VERSION 5.7 ;
  NOWIREEXTENSIONATPIN ON ;
  DIVIDERCHAR "/" ;
  BUSBITCHARS "[]" ;
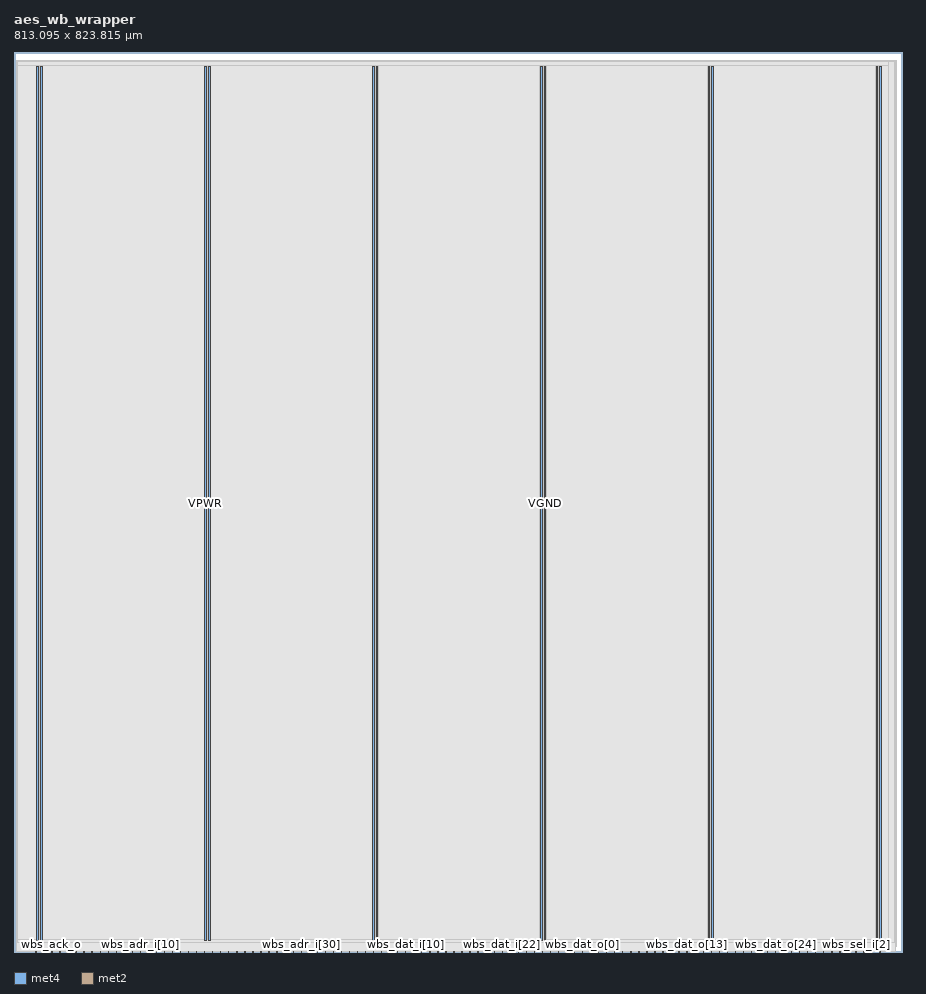
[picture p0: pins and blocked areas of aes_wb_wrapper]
MACRO aes_wb_wrapper
  CLASS BLOCK ;
  FOREIGN aes_wb_wrapper ;
  ORIGIN 0.000 0.000 ;
  SIZE 813.095 BY 823.815 ;
  PIN VGND
    DIRECTION INOUT ;
    USE GROUND ;
    PORT
      LAYER met4 ;
        RECT 24.340 10.640 25.940 810.800 ;
    END
    PORT
      LAYER met4 ;
        RECT 177.940 10.640 179.540 810.800 ;
    END
    PORT
      LAYER met4 ;
        RECT 331.540 10.640 333.140 810.800 ;
    END
    PORT
      LAYER met4 ;
        RECT 485.140 10.640 486.740 810.800 ;
    END
    PORT
      LAYER met4 ;
        RECT 638.740 10.640 640.340 810.800 ;
    END
    PORT
      LAYER met4 ;
        RECT 792.340 10.640 793.940 810.800 ;
    END
  END VGND
  PIN VPWR
    DIRECTION INOUT ;
    USE POWER ;
    PORT
      LAYER met4 ;
        RECT 21.040 10.640 22.640 810.800 ;
    END
    PORT
      LAYER met4 ;
        RECT 174.640 10.640 176.240 810.800 ;
    END
    PORT
      LAYER met4 ;
        RECT 328.240 10.640 329.840 810.800 ;
    END
    PORT
      LAYER met4 ;
        RECT 481.840 10.640 483.440 810.800 ;
    END
    PORT
      LAYER met4 ;
        RECT 635.440 10.640 637.040 810.800 ;
    END
    PORT
      LAYER met4 ;
        RECT 789.040 10.640 790.640 810.800 ;
    END
  END VPWR
  PIN wb_clk_i
    DIRECTION INPUT ;
    USE SIGNAL ;
    ANTENNAGATEAREA 1.286700 ;
    ANTENNADIFFAREA 0.434700 ;
    PORT
      LAYER met2 ;
        RECT 19.870 0.000 20.150 0.280 ;
    END
  END wb_clk_i
  PIN wb_rst_i
    DIRECTION INPUT ;
    USE SIGNAL ;
    ANTENNAGATEAREA 0.593700 ;
    ANTENNADIFFAREA 0.434700 ;
    PORT
      LAYER met2 ;
        RECT 27.230 0.000 27.510 0.280 ;
    END
  END wb_rst_i
  PIN wbs_ack_o
    DIRECTION OUTPUT ;
    USE SIGNAL ;
    ANTENNADIFFAREA 2.673000 ;
    PORT
      LAYER met2 ;
        RECT 34.590 0.000 34.870 0.280 ;
    END
  END wbs_ack_o
  PIN wbs_adr_i[0]
    DIRECTION INPUT ;
    USE SIGNAL ;
    PORT
      LAYER met2 ;
        RECT 41.950 0.000 42.230 0.280 ;
    END
  END wbs_adr_i[0]
  PIN wbs_adr_i[10]
    DIRECTION INPUT ;
    USE SIGNAL ;
    PORT
      LAYER met2 ;
        RECT 115.550 0.000 115.830 0.280 ;
    END
  END wbs_adr_i[10]
  PIN wbs_adr_i[11]
    DIRECTION INPUT ;
    USE SIGNAL ;
    PORT
      LAYER met2 ;
        RECT 122.910 0.000 123.190 0.280 ;
    END
  END wbs_adr_i[11]
  PIN wbs_adr_i[12]
    DIRECTION INPUT ;
    USE SIGNAL ;
    PORT
      LAYER met2 ;
        RECT 130.270 0.000 130.550 0.280 ;
    END
  END wbs_adr_i[12]
  PIN wbs_adr_i[13]
    DIRECTION INPUT ;
    USE SIGNAL ;
    PORT
      LAYER met2 ;
        RECT 137.630 0.000 137.910 0.280 ;
    END
  END wbs_adr_i[13]
  PIN wbs_adr_i[14]
    DIRECTION INPUT ;
    USE SIGNAL ;
    PORT
      LAYER met2 ;
        RECT 144.990 0.000 145.270 0.280 ;
    END
  END wbs_adr_i[14]
  PIN wbs_adr_i[15]
    DIRECTION INPUT ;
    USE SIGNAL ;
    PORT
      LAYER met2 ;
        RECT 152.350 0.000 152.630 0.280 ;
    END
  END wbs_adr_i[15]
  PIN wbs_adr_i[16]
    DIRECTION INPUT ;
    USE SIGNAL ;
    PORT
      LAYER met2 ;
        RECT 159.710 0.000 159.990 0.280 ;
    END
  END wbs_adr_i[16]
  PIN wbs_adr_i[17]
    DIRECTION INPUT ;
    USE SIGNAL ;
    PORT
      LAYER met2 ;
        RECT 167.070 0.000 167.350 0.280 ;
    END
  END wbs_adr_i[17]
  PIN wbs_adr_i[18]
    DIRECTION INPUT ;
    USE SIGNAL ;
    PORT
      LAYER met2 ;
        RECT 174.430 0.000 174.710 0.280 ;
    END
  END wbs_adr_i[18]
  PIN wbs_adr_i[19]
    DIRECTION INPUT ;
    USE SIGNAL ;
    PORT
      LAYER met2 ;
        RECT 181.790 0.000 182.070 0.280 ;
    END
  END wbs_adr_i[19]
  PIN wbs_adr_i[1]
    DIRECTION INPUT ;
    USE SIGNAL ;
    PORT
      LAYER met2 ;
        RECT 49.310 0.000 49.590 0.280 ;
    END
  END wbs_adr_i[1]
  PIN wbs_adr_i[20]
    DIRECTION INPUT ;
    USE SIGNAL ;
    PORT
      LAYER met2 ;
        RECT 189.150 0.000 189.430 0.280 ;
    END
  END wbs_adr_i[20]
  PIN wbs_adr_i[21]
    DIRECTION INPUT ;
    USE SIGNAL ;
    PORT
      LAYER met2 ;
        RECT 196.510 0.000 196.790 0.280 ;
    END
  END wbs_adr_i[21]
  PIN wbs_adr_i[22]
    DIRECTION INPUT ;
    USE SIGNAL ;
    PORT
      LAYER met2 ;
        RECT 203.870 0.000 204.150 0.280 ;
    END
  END wbs_adr_i[22]
  PIN wbs_adr_i[23]
    DIRECTION INPUT ;
    USE SIGNAL ;
    PORT
      LAYER met2 ;
        RECT 211.230 0.000 211.510 0.280 ;
    END
  END wbs_adr_i[23]
  PIN wbs_adr_i[24]
    DIRECTION INPUT ;
    USE SIGNAL ;
    PORT
      LAYER met2 ;
        RECT 218.590 0.000 218.870 0.280 ;
    END
  END wbs_adr_i[24]
  PIN wbs_adr_i[25]
    DIRECTION INPUT ;
    USE SIGNAL ;
    PORT
      LAYER met2 ;
        RECT 225.950 0.000 226.230 0.280 ;
    END
  END wbs_adr_i[25]
  PIN wbs_adr_i[26]
    DIRECTION INPUT ;
    USE SIGNAL ;
    PORT
      LAYER met2 ;
        RECT 233.310 0.000 233.590 0.280 ;
    END
  END wbs_adr_i[26]
  PIN wbs_adr_i[27]
    DIRECTION INPUT ;
    USE SIGNAL ;
    PORT
      LAYER met2 ;
        RECT 240.670 0.000 240.950 0.280 ;
    END
  END wbs_adr_i[27]
  PIN wbs_adr_i[28]
    DIRECTION INPUT ;
    USE SIGNAL ;
    PORT
      LAYER met2 ;
        RECT 248.030 0.000 248.310 0.280 ;
    END
  END wbs_adr_i[28]
  PIN wbs_adr_i[29]
    DIRECTION INPUT ;
    USE SIGNAL ;
    PORT
      LAYER met2 ;
        RECT 255.390 0.000 255.670 0.280 ;
    END
  END wbs_adr_i[29]
  PIN wbs_adr_i[2]
    DIRECTION INPUT ;
    USE SIGNAL ;
    ANTENNAGATEAREA 0.560700 ;
    ANTENNADIFFAREA 0.434700 ;
    PORT
      LAYER met2 ;
        RECT 56.670 0.000 56.950 0.280 ;
    END
  END wbs_adr_i[2]
  PIN wbs_adr_i[30]
    DIRECTION INPUT ;
    USE SIGNAL ;
    PORT
      LAYER met2 ;
        RECT 262.750 0.000 263.030 0.280 ;
    END
  END wbs_adr_i[30]
  PIN wbs_adr_i[31]
    DIRECTION INPUT ;
    USE SIGNAL ;
    PORT
      LAYER met2 ;
        RECT 270.110 0.000 270.390 0.280 ;
    END
  END wbs_adr_i[31]
  PIN wbs_adr_i[3]
    DIRECTION INPUT ;
    USE SIGNAL ;
    ANTENNAGATEAREA 0.560700 ;
    ANTENNADIFFAREA 0.434700 ;
    PORT
      LAYER met2 ;
        RECT 64.030 0.000 64.310 0.280 ;
    END
  END wbs_adr_i[3]
  PIN wbs_adr_i[4]
    DIRECTION INPUT ;
    USE SIGNAL ;
    ANTENNAGATEAREA 0.560700 ;
    ANTENNADIFFAREA 0.434700 ;
    PORT
      LAYER met2 ;
        RECT 71.390 0.000 71.670 0.280 ;
    END
  END wbs_adr_i[4]
  PIN wbs_adr_i[5]
    DIRECTION INPUT ;
    USE SIGNAL ;
    ANTENNAGATEAREA 0.560700 ;
    ANTENNADIFFAREA 0.434700 ;
    PORT
      LAYER met2 ;
        RECT 78.750 0.000 79.030 0.280 ;
    END
  END wbs_adr_i[5]
  PIN wbs_adr_i[6]
    DIRECTION INPUT ;
    USE SIGNAL ;
    ANTENNAGATEAREA 0.560700 ;
    ANTENNADIFFAREA 0.434700 ;
    PORT
      LAYER met2 ;
        RECT 86.110 0.000 86.390 0.280 ;
    END
  END wbs_adr_i[6]
  PIN wbs_adr_i[7]
    DIRECTION INPUT ;
    USE SIGNAL ;
    ANTENNAGATEAREA 0.560700 ;
    ANTENNADIFFAREA 0.434700 ;
    PORT
      LAYER met2 ;
        RECT 93.470 0.000 93.750 0.280 ;
    END
  END wbs_adr_i[7]
  PIN wbs_adr_i[8]
    DIRECTION INPUT ;
    USE SIGNAL ;
    ANTENNAGATEAREA 0.560700 ;
    ANTENNADIFFAREA 0.434700 ;
    PORT
      LAYER met2 ;
        RECT 100.830 0.000 101.110 0.280 ;
    END
  END wbs_adr_i[8]
  PIN wbs_adr_i[9]
    DIRECTION INPUT ;
    USE SIGNAL ;
    ANTENNAGATEAREA 0.647700 ;
    ANTENNADIFFAREA 0.434700 ;
    PORT
      LAYER met2 ;
        RECT 108.190 0.000 108.470 0.280 ;
    END
  END wbs_adr_i[9]
  PIN wbs_cyc_i
    DIRECTION INPUT ;
    USE SIGNAL ;
    ANTENNAGATEAREA 0.560700 ;
    ANTENNADIFFAREA 0.434700 ;
    PORT
      LAYER met2 ;
        RECT 277.470 0.000 277.750 0.280 ;
    END
  END wbs_cyc_i
  PIN wbs_dat_i[0]
    DIRECTION INPUT ;
    USE SIGNAL ;
    ANTENNAGATEAREA 0.560700 ;
    ANTENNADIFFAREA 0.434700 ;
    PORT
      LAYER met2 ;
        RECT 284.830 0.000 285.110 0.280 ;
    END
  END wbs_dat_i[0]
  PIN wbs_dat_i[10]
    DIRECTION INPUT ;
    USE SIGNAL ;
    ANTENNAGATEAREA 0.560700 ;
    ANTENNADIFFAREA 0.434700 ;
    PORT
      LAYER met2 ;
        RECT 358.430 0.000 358.710 0.280 ;
    END
  END wbs_dat_i[10]
  PIN wbs_dat_i[11]
    DIRECTION INPUT ;
    USE SIGNAL ;
    ANTENNAGATEAREA 0.560700 ;
    ANTENNADIFFAREA 0.434700 ;
    PORT
      LAYER met2 ;
        RECT 365.790 0.000 366.070 0.280 ;
    END
  END wbs_dat_i[11]
  PIN wbs_dat_i[12]
    DIRECTION INPUT ;
    USE SIGNAL ;
    ANTENNAGATEAREA 0.560700 ;
    ANTENNADIFFAREA 0.434700 ;
    PORT
      LAYER met2 ;
        RECT 373.150 0.000 373.430 0.280 ;
    END
  END wbs_dat_i[12]
  PIN wbs_dat_i[13]
    DIRECTION INPUT ;
    USE SIGNAL ;
    ANTENNAGATEAREA 0.560700 ;
    ANTENNADIFFAREA 0.434700 ;
    PORT
      LAYER met2 ;
        RECT 380.510 0.000 380.790 0.280 ;
    END
  END wbs_dat_i[13]
  PIN wbs_dat_i[14]
    DIRECTION INPUT ;
    USE SIGNAL ;
    ANTENNAGATEAREA 0.560700 ;
    ANTENNADIFFAREA 0.434700 ;
    PORT
      LAYER met2 ;
        RECT 387.870 0.000 388.150 0.280 ;
    END
  END wbs_dat_i[14]
  PIN wbs_dat_i[15]
    DIRECTION INPUT ;
    USE SIGNAL ;
    ANTENNAGATEAREA 0.560700 ;
    ANTENNADIFFAREA 0.434700 ;
    PORT
      LAYER met2 ;
        RECT 395.230 0.000 395.510 0.280 ;
    END
  END wbs_dat_i[15]
  PIN wbs_dat_i[16]
    DIRECTION INPUT ;
    USE SIGNAL ;
    ANTENNAGATEAREA 0.560700 ;
    ANTENNADIFFAREA 0.434700 ;
    PORT
      LAYER met2 ;
        RECT 402.590 0.000 402.870 0.280 ;
    END
  END wbs_dat_i[16]
  PIN wbs_dat_i[17]
    DIRECTION INPUT ;
    USE SIGNAL ;
    ANTENNAGATEAREA 0.560700 ;
    ANTENNADIFFAREA 0.434700 ;
    PORT
      LAYER met2 ;
        RECT 409.950 0.000 410.230 0.280 ;
    END
  END wbs_dat_i[17]
  PIN wbs_dat_i[18]
    DIRECTION INPUT ;
    USE SIGNAL ;
    ANTENNAGATEAREA 0.560700 ;
    ANTENNADIFFAREA 0.434700 ;
    PORT
      LAYER met2 ;
        RECT 417.310 0.000 417.590 0.280 ;
    END
  END wbs_dat_i[18]
  PIN wbs_dat_i[19]
    DIRECTION INPUT ;
    USE SIGNAL ;
    ANTENNAGATEAREA 0.560700 ;
    ANTENNADIFFAREA 0.434700 ;
    PORT
      LAYER met2 ;
        RECT 424.670 0.000 424.950 0.280 ;
    END
  END wbs_dat_i[19]
  PIN wbs_dat_i[1]
    DIRECTION INPUT ;
    USE SIGNAL ;
    ANTENNAGATEAREA 0.560700 ;
    ANTENNADIFFAREA 0.434700 ;
    PORT
      LAYER met2 ;
        RECT 292.190 0.000 292.470 0.280 ;
    END
  END wbs_dat_i[1]
  PIN wbs_dat_i[20]
    DIRECTION INPUT ;
    USE SIGNAL ;
    ANTENNAGATEAREA 0.560700 ;
    ANTENNADIFFAREA 0.434700 ;
    PORT
      LAYER met2 ;
        RECT 432.030 0.000 432.310 0.280 ;
    END
  END wbs_dat_i[20]
  PIN wbs_dat_i[21]
    DIRECTION INPUT ;
    USE SIGNAL ;
    ANTENNAGATEAREA 0.560700 ;
    ANTENNADIFFAREA 0.434700 ;
    PORT
      LAYER met2 ;
        RECT 439.390 0.000 439.670 0.280 ;
    END
  END wbs_dat_i[21]
  PIN wbs_dat_i[22]
    DIRECTION INPUT ;
    USE SIGNAL ;
    ANTENNAGATEAREA 0.560700 ;
    ANTENNADIFFAREA 0.434700 ;
    PORT
      LAYER met2 ;
        RECT 446.750 0.000 447.030 0.280 ;
    END
  END wbs_dat_i[22]
  PIN wbs_dat_i[23]
    DIRECTION INPUT ;
    USE SIGNAL ;
    ANTENNAGATEAREA 0.560700 ;
    ANTENNADIFFAREA 0.434700 ;
    PORT
      LAYER met2 ;
        RECT 454.110 0.000 454.390 0.280 ;
    END
  END wbs_dat_i[23]
  PIN wbs_dat_i[24]
    DIRECTION INPUT ;
    USE SIGNAL ;
    ANTENNAGATEAREA 0.560700 ;
    ANTENNADIFFAREA 0.434700 ;
    PORT
      LAYER met2 ;
        RECT 461.470 0.000 461.750 0.280 ;
    END
  END wbs_dat_i[24]
  PIN wbs_dat_i[25]
    DIRECTION INPUT ;
    USE SIGNAL ;
    ANTENNAGATEAREA 0.560700 ;
    ANTENNADIFFAREA 0.434700 ;
    PORT
      LAYER met2 ;
        RECT 468.830 0.000 469.110 0.280 ;
    END
  END wbs_dat_i[25]
  PIN wbs_dat_i[26]
    DIRECTION INPUT ;
    USE SIGNAL ;
    ANTENNAGATEAREA 0.560700 ;
    ANTENNADIFFAREA 0.434700 ;
    PORT
      LAYER met2 ;
        RECT 476.190 0.000 476.470 0.280 ;
    END
  END wbs_dat_i[26]
  PIN wbs_dat_i[27]
    DIRECTION INPUT ;
    USE SIGNAL ;
    ANTENNAGATEAREA 0.560700 ;
    ANTENNADIFFAREA 0.434700 ;
    PORT
      LAYER met2 ;
        RECT 483.550 0.000 483.830 0.280 ;
    END
  END wbs_dat_i[27]
  PIN wbs_dat_i[28]
    DIRECTION INPUT ;
    USE SIGNAL ;
    ANTENNAGATEAREA 0.560700 ;
    ANTENNADIFFAREA 0.434700 ;
    PORT
      LAYER met2 ;
        RECT 490.910 0.000 491.190 0.280 ;
    END
  END wbs_dat_i[28]
  PIN wbs_dat_i[29]
    DIRECTION INPUT ;
    USE SIGNAL ;
    ANTENNAGATEAREA 0.560700 ;
    ANTENNADIFFAREA 0.434700 ;
    PORT
      LAYER met2 ;
        RECT 498.270 0.000 498.550 0.280 ;
    END
  END wbs_dat_i[29]
  PIN wbs_dat_i[2]
    DIRECTION INPUT ;
    USE SIGNAL ;
    ANTENNAGATEAREA 0.560700 ;
    ANTENNADIFFAREA 0.434700 ;
    PORT
      LAYER met2 ;
        RECT 299.550 0.000 299.830 0.280 ;
    END
  END wbs_dat_i[2]
  PIN wbs_dat_i[30]
    DIRECTION INPUT ;
    USE SIGNAL ;
    ANTENNAGATEAREA 0.560700 ;
    ANTENNADIFFAREA 0.434700 ;
    PORT
      LAYER met2 ;
        RECT 505.630 0.000 505.910 0.280 ;
    END
  END wbs_dat_i[30]
  PIN wbs_dat_i[31]
    DIRECTION INPUT ;
    USE SIGNAL ;
    ANTENNAGATEAREA 0.560700 ;
    ANTENNADIFFAREA 0.434700 ;
    PORT
      LAYER met2 ;
        RECT 512.990 0.000 513.270 0.280 ;
    END
  END wbs_dat_i[31]
  PIN wbs_dat_i[3]
    DIRECTION INPUT ;
    USE SIGNAL ;
    ANTENNAGATEAREA 0.560700 ;
    ANTENNADIFFAREA 0.434700 ;
    PORT
      LAYER met2 ;
        RECT 306.910 0.000 307.190 0.280 ;
    END
  END wbs_dat_i[3]
  PIN wbs_dat_i[4]
    DIRECTION INPUT ;
    USE SIGNAL ;
    ANTENNAGATEAREA 0.560700 ;
    ANTENNADIFFAREA 0.434700 ;
    PORT
      LAYER met2 ;
        RECT 314.270 0.000 314.550 0.280 ;
    END
  END wbs_dat_i[4]
  PIN wbs_dat_i[5]
    DIRECTION INPUT ;
    USE SIGNAL ;
    ANTENNAGATEAREA 0.560700 ;
    ANTENNADIFFAREA 0.434700 ;
    PORT
      LAYER met2 ;
        RECT 321.630 0.000 321.910 0.280 ;
    END
  END wbs_dat_i[5]
  PIN wbs_dat_i[6]
    DIRECTION INPUT ;
    USE SIGNAL ;
    ANTENNAGATEAREA 0.560700 ;
    ANTENNADIFFAREA 0.434700 ;
    PORT
      LAYER met2 ;
        RECT 328.990 0.000 329.270 0.280 ;
    END
  END wbs_dat_i[6]
  PIN wbs_dat_i[7]
    DIRECTION INPUT ;
    USE SIGNAL ;
    ANTENNAGATEAREA 0.560700 ;
    ANTENNADIFFAREA 0.434700 ;
    PORT
      LAYER met2 ;
        RECT 336.350 0.000 336.630 0.280 ;
    END
  END wbs_dat_i[7]
  PIN wbs_dat_i[8]
    DIRECTION INPUT ;
    USE SIGNAL ;
    ANTENNAGATEAREA 0.560700 ;
    ANTENNADIFFAREA 0.434700 ;
    PORT
      LAYER met2 ;
        RECT 343.710 0.000 343.990 0.280 ;
    END
  END wbs_dat_i[8]
  PIN wbs_dat_i[9]
    DIRECTION INPUT ;
    USE SIGNAL ;
    ANTENNAGATEAREA 0.560700 ;
    ANTENNADIFFAREA 0.434700 ;
    PORT
      LAYER met2 ;
        RECT 351.070 0.000 351.350 0.280 ;
    END
  END wbs_dat_i[9]
  PIN wbs_dat_o[0]
    DIRECTION OUTPUT ;
    USE SIGNAL ;
    ANTENNADIFFAREA 2.673000 ;
    PORT
      LAYER met2 ;
        RECT 520.350 0.000 520.630 0.280 ;
    END
  END wbs_dat_o[0]
  PIN wbs_dat_o[10]
    DIRECTION OUTPUT ;
    USE SIGNAL ;
    ANTENNADIFFAREA 2.673000 ;
    PORT
      LAYER met2 ;
        RECT 593.950 0.000 594.230 0.280 ;
    END
  END wbs_dat_o[10]
  PIN wbs_dat_o[11]
    DIRECTION OUTPUT ;
    USE SIGNAL ;
    ANTENNADIFFAREA 2.673000 ;
    PORT
      LAYER met2 ;
        RECT 601.310 0.000 601.590 0.280 ;
    END
  END wbs_dat_o[11]
  PIN wbs_dat_o[12]
    DIRECTION OUTPUT ;
    USE SIGNAL ;
    ANTENNADIFFAREA 2.673000 ;
    PORT
      LAYER met2 ;
        RECT 608.670 0.000 608.950 0.280 ;
    END
  END wbs_dat_o[12]
  PIN wbs_dat_o[13]
    DIRECTION OUTPUT ;
    USE SIGNAL ;
    ANTENNADIFFAREA 2.673000 ;
    PORT
      LAYER met2 ;
        RECT 616.030 0.000 616.310 0.280 ;
    END
  END wbs_dat_o[13]
  PIN wbs_dat_o[14]
    DIRECTION OUTPUT ;
    USE SIGNAL ;
    ANTENNADIFFAREA 2.673000 ;
    PORT
      LAYER met2 ;
        RECT 623.390 0.000 623.670 0.280 ;
    END
  END wbs_dat_o[14]
  PIN wbs_dat_o[15]
    DIRECTION OUTPUT ;
    USE SIGNAL ;
    ANTENNADIFFAREA 2.673000 ;
    PORT
      LAYER met2 ;
        RECT 630.750 0.000 631.030 0.280 ;
    END
  END wbs_dat_o[15]
  PIN wbs_dat_o[16]
    DIRECTION OUTPUT ;
    USE SIGNAL ;
    ANTENNADIFFAREA 2.673000 ;
    PORT
      LAYER met2 ;
        RECT 638.110 0.000 638.390 0.280 ;
    END
  END wbs_dat_o[16]
  PIN wbs_dat_o[17]
    DIRECTION OUTPUT ;
    USE SIGNAL ;
    ANTENNADIFFAREA 2.673000 ;
    PORT
      LAYER met2 ;
        RECT 645.470 0.000 645.750 0.280 ;
    END
  END wbs_dat_o[17]
  PIN wbs_dat_o[18]
    DIRECTION OUTPUT ;
    USE SIGNAL ;
    ANTENNADIFFAREA 2.673000 ;
    PORT
      LAYER met2 ;
        RECT 652.830 0.000 653.110 0.280 ;
    END
  END wbs_dat_o[18]
  PIN wbs_dat_o[19]
    DIRECTION OUTPUT ;
    USE SIGNAL ;
    ANTENNADIFFAREA 2.673000 ;
    PORT
      LAYER met2 ;
        RECT 660.190 0.000 660.470 0.280 ;
    END
  END wbs_dat_o[19]
  PIN wbs_dat_o[1]
    DIRECTION OUTPUT ;
    USE SIGNAL ;
    ANTENNADIFFAREA 2.673000 ;
    PORT
      LAYER met2 ;
        RECT 527.710 0.000 527.990 0.280 ;
    END
  END wbs_dat_o[1]
  PIN wbs_dat_o[20]
    DIRECTION OUTPUT ;
    USE SIGNAL ;
    ANTENNADIFFAREA 2.673000 ;
    PORT
      LAYER met2 ;
        RECT 667.550 0.000 667.830 0.280 ;
    END
  END wbs_dat_o[20]
  PIN wbs_dat_o[21]
    DIRECTION OUTPUT ;
    USE SIGNAL ;
    ANTENNADIFFAREA 2.673000 ;
    PORT
      LAYER met2 ;
        RECT 674.910 0.000 675.190 0.280 ;
    END
  END wbs_dat_o[21]
  PIN wbs_dat_o[22]
    DIRECTION OUTPUT ;
    USE SIGNAL ;
    ANTENNADIFFAREA 2.673000 ;
    PORT
      LAYER met2 ;
        RECT 682.270 0.000 682.550 0.280 ;
    END
  END wbs_dat_o[22]
  PIN wbs_dat_o[23]
    DIRECTION OUTPUT ;
    USE SIGNAL ;
    ANTENNADIFFAREA 2.673000 ;
    PORT
      LAYER met2 ;
        RECT 689.630 0.000 689.910 0.280 ;
    END
  END wbs_dat_o[23]
  PIN wbs_dat_o[24]
    DIRECTION OUTPUT ;
    USE SIGNAL ;
    ANTENNADIFFAREA 2.673000 ;
    PORT
      LAYER met2 ;
        RECT 696.990 0.000 697.270 0.280 ;
    END
  END wbs_dat_o[24]
  PIN wbs_dat_o[25]
    DIRECTION OUTPUT ;
    USE SIGNAL ;
    ANTENNADIFFAREA 2.673000 ;
    PORT
      LAYER met2 ;
        RECT 704.350 0.000 704.630 0.280 ;
    END
  END wbs_dat_o[25]
  PIN wbs_dat_o[26]
    DIRECTION OUTPUT ;
    USE SIGNAL ;
    ANTENNADIFFAREA 2.673000 ;
    PORT
      LAYER met2 ;
        RECT 711.710 0.000 711.990 0.280 ;
    END
  END wbs_dat_o[26]
  PIN wbs_dat_o[27]
    DIRECTION OUTPUT ;
    USE SIGNAL ;
    ANTENNADIFFAREA 2.673000 ;
    PORT
      LAYER met2 ;
        RECT 719.070 0.000 719.350 0.280 ;
    END
  END wbs_dat_o[27]
  PIN wbs_dat_o[28]
    DIRECTION OUTPUT ;
    USE SIGNAL ;
    ANTENNADIFFAREA 2.673000 ;
    PORT
      LAYER met2 ;
        RECT 726.430 0.000 726.710 0.280 ;
    END
  END wbs_dat_o[28]
  PIN wbs_dat_o[29]
    DIRECTION OUTPUT ;
    USE SIGNAL ;
    ANTENNADIFFAREA 2.673000 ;
    PORT
      LAYER met2 ;
        RECT 733.790 0.000 734.070 0.280 ;
    END
  END wbs_dat_o[29]
  PIN wbs_dat_o[2]
    DIRECTION OUTPUT ;
    USE SIGNAL ;
    ANTENNADIFFAREA 2.673000 ;
    PORT
      LAYER met2 ;
        RECT 535.070 0.000 535.350 0.280 ;
    END
  END wbs_dat_o[2]
  PIN wbs_dat_o[30]
    DIRECTION OUTPUT ;
    USE SIGNAL ;
    ANTENNADIFFAREA 2.673000 ;
    PORT
      LAYER met2 ;
        RECT 741.150 0.000 741.430 0.280 ;
    END
  END wbs_dat_o[30]
  PIN wbs_dat_o[31]
    DIRECTION OUTPUT ;
    USE SIGNAL ;
    ANTENNADIFFAREA 2.673000 ;
    PORT
      LAYER met2 ;
        RECT 748.510 0.000 748.790 0.280 ;
    END
  END wbs_dat_o[31]
  PIN wbs_dat_o[3]
    DIRECTION OUTPUT ;
    USE SIGNAL ;
    ANTENNADIFFAREA 2.673000 ;
    PORT
      LAYER met2 ;
        RECT 542.430 0.000 542.710 0.280 ;
    END
  END wbs_dat_o[3]
  PIN wbs_dat_o[4]
    DIRECTION OUTPUT ;
    USE SIGNAL ;
    ANTENNADIFFAREA 2.673000 ;
    PORT
      LAYER met2 ;
        RECT 549.790 0.000 550.070 0.280 ;
    END
  END wbs_dat_o[4]
  PIN wbs_dat_o[5]
    DIRECTION OUTPUT ;
    USE SIGNAL ;
    ANTENNADIFFAREA 2.673000 ;
    PORT
      LAYER met2 ;
        RECT 557.150 0.000 557.430 0.280 ;
    END
  END wbs_dat_o[5]
  PIN wbs_dat_o[6]
    DIRECTION OUTPUT ;
    USE SIGNAL ;
    ANTENNADIFFAREA 2.673000 ;
    PORT
      LAYER met2 ;
        RECT 564.510 0.000 564.790 0.280 ;
    END
  END wbs_dat_o[6]
  PIN wbs_dat_o[7]
    DIRECTION OUTPUT ;
    USE SIGNAL ;
    ANTENNADIFFAREA 2.673000 ;
    PORT
      LAYER met2 ;
        RECT 571.870 0.000 572.150 0.280 ;
    END
  END wbs_dat_o[7]
  PIN wbs_dat_o[8]
    DIRECTION OUTPUT ;
    USE SIGNAL ;
    ANTENNADIFFAREA 2.673000 ;
    PORT
      LAYER met2 ;
        RECT 579.230 0.000 579.510 0.280 ;
    END
  END wbs_dat_o[8]
  PIN wbs_dat_o[9]
    DIRECTION OUTPUT ;
    USE SIGNAL ;
    ANTENNADIFFAREA 2.673000 ;
    PORT
      LAYER met2 ;
        RECT 586.590 0.000 586.870 0.280 ;
    END
  END wbs_dat_o[9]
  PIN wbs_sel_i[0]
    DIRECTION INPUT ;
    USE SIGNAL ;
    PORT
      LAYER met2 ;
        RECT 755.870 0.000 756.150 0.280 ;
    END
  END wbs_sel_i[0]
  PIN wbs_sel_i[1]
    DIRECTION INPUT ;
    USE SIGNAL ;
    PORT
      LAYER met2 ;
        RECT 763.230 0.000 763.510 0.280 ;
    END
  END wbs_sel_i[1]
  PIN wbs_sel_i[2]
    DIRECTION INPUT ;
    USE SIGNAL ;
    PORT
      LAYER met2 ;
        RECT 770.590 0.000 770.870 0.280 ;
    END
  END wbs_sel_i[2]
  PIN wbs_sel_i[3]
    DIRECTION INPUT ;
    USE SIGNAL ;
    PORT
      LAYER met2 ;
        RECT 777.950 0.000 778.230 0.280 ;
    END
  END wbs_sel_i[3]
  PIN wbs_stb_i
    DIRECTION INPUT ;
    USE SIGNAL ;
    ANTENNAGATEAREA 0.560700 ;
    ANTENNADIFFAREA 0.434700 ;
    PORT
      LAYER met2 ;
        RECT 785.310 0.000 785.590 0.280 ;
    END
  END wbs_stb_i
  PIN wbs_we_i
    DIRECTION INPUT ;
    USE SIGNAL ;
    ANTENNAGATEAREA 0.631200 ;
    ANTENNADIFFAREA 0.434700 ;
    PORT
      LAYER met2 ;
        RECT 792.670 0.000 792.950 0.280 ;
    END
  END wbs_we_i
  OBS
      LAYER nwell ;
        RECT 5.330 10.795 807.490 810.645 ;
      LAYER li1 ;
        RECT 5.520 10.795 807.300 810.645 ;
      LAYER met1 ;
        RECT 1.910 5.480 807.600 815.620 ;
      LAYER met2 ;
        RECT 1.940 0.560 806.740 815.650 ;
        RECT 1.940 0.070 19.590 0.560 ;
        RECT 20.430 0.070 26.950 0.560 ;
        RECT 27.790 0.070 34.310 0.560 ;
        RECT 35.150 0.070 41.670 0.560 ;
        RECT 42.510 0.070 49.030 0.560 ;
        RECT 49.870 0.070 56.390 0.560 ;
        RECT 57.230 0.070 63.750 0.560 ;
        RECT 64.590 0.070 71.110 0.560 ;
        RECT 71.950 0.070 78.470 0.560 ;
        RECT 79.310 0.070 85.830 0.560 ;
        RECT 86.670 0.070 93.190 0.560 ;
        RECT 94.030 0.070 100.550 0.560 ;
        RECT 101.390 0.070 107.910 0.560 ;
        RECT 108.750 0.070 115.270 0.560 ;
        RECT 116.110 0.070 122.630 0.560 ;
        RECT 123.470 0.070 129.990 0.560 ;
        RECT 130.830 0.070 137.350 0.560 ;
        RECT 138.190 0.070 144.710 0.560 ;
        RECT 145.550 0.070 152.070 0.560 ;
        RECT 152.910 0.070 159.430 0.560 ;
        RECT 160.270 0.070 166.790 0.560 ;
        RECT 167.630 0.070 174.150 0.560 ;
        RECT 174.990 0.070 181.510 0.560 ;
        RECT 182.350 0.070 188.870 0.560 ;
        RECT 189.710 0.070 196.230 0.560 ;
        RECT 197.070 0.070 203.590 0.560 ;
        RECT 204.430 0.070 210.950 0.560 ;
        RECT 211.790 0.070 218.310 0.560 ;
        RECT 219.150 0.070 225.670 0.560 ;
        RECT 226.510 0.070 233.030 0.560 ;
        RECT 233.870 0.070 240.390 0.560 ;
        RECT 241.230 0.070 247.750 0.560 ;
        RECT 248.590 0.070 255.110 0.560 ;
        RECT 255.950 0.070 262.470 0.560 ;
        RECT 263.310 0.070 269.830 0.560 ;
        RECT 270.670 0.070 277.190 0.560 ;
        RECT 278.030 0.070 284.550 0.560 ;
        RECT 285.390 0.070 291.910 0.560 ;
        RECT 292.750 0.070 299.270 0.560 ;
        RECT 300.110 0.070 306.630 0.560 ;
        RECT 307.470 0.070 313.990 0.560 ;
        RECT 314.830 0.070 321.350 0.560 ;
        RECT 322.190 0.070 328.710 0.560 ;
        RECT 329.550 0.070 336.070 0.560 ;
        RECT 336.910 0.070 343.430 0.560 ;
        RECT 344.270 0.070 350.790 0.560 ;
        RECT 351.630 0.070 358.150 0.560 ;
        RECT 358.990 0.070 365.510 0.560 ;
        RECT 366.350 0.070 372.870 0.560 ;
        RECT 373.710 0.070 380.230 0.560 ;
        RECT 381.070 0.070 387.590 0.560 ;
        RECT 388.430 0.070 394.950 0.560 ;
        RECT 395.790 0.070 402.310 0.560 ;
        RECT 403.150 0.070 409.670 0.560 ;
        RECT 410.510 0.070 417.030 0.560 ;
        RECT 417.870 0.070 424.390 0.560 ;
        RECT 425.230 0.070 431.750 0.560 ;
        RECT 432.590 0.070 439.110 0.560 ;
        RECT 439.950 0.070 446.470 0.560 ;
        RECT 447.310 0.070 453.830 0.560 ;
        RECT 454.670 0.070 461.190 0.560 ;
        RECT 462.030 0.070 468.550 0.560 ;
        RECT 469.390 0.070 475.910 0.560 ;
        RECT 476.750 0.070 483.270 0.560 ;
        RECT 484.110 0.070 490.630 0.560 ;
        RECT 491.470 0.070 497.990 0.560 ;
        RECT 498.830 0.070 505.350 0.560 ;
        RECT 506.190 0.070 512.710 0.560 ;
        RECT 513.550 0.070 520.070 0.560 ;
        RECT 520.910 0.070 527.430 0.560 ;
        RECT 528.270 0.070 534.790 0.560 ;
        RECT 535.630 0.070 542.150 0.560 ;
        RECT 542.990 0.070 549.510 0.560 ;
        RECT 550.350 0.070 556.870 0.560 ;
        RECT 557.710 0.070 564.230 0.560 ;
        RECT 565.070 0.070 571.590 0.560 ;
        RECT 572.430 0.070 578.950 0.560 ;
        RECT 579.790 0.070 586.310 0.560 ;
        RECT 587.150 0.070 593.670 0.560 ;
        RECT 594.510 0.070 601.030 0.560 ;
        RECT 601.870 0.070 608.390 0.560 ;
        RECT 609.230 0.070 615.750 0.560 ;
        RECT 616.590 0.070 623.110 0.560 ;
        RECT 623.950 0.070 630.470 0.560 ;
        RECT 631.310 0.070 637.830 0.560 ;
        RECT 638.670 0.070 645.190 0.560 ;
        RECT 646.030 0.070 652.550 0.560 ;
        RECT 653.390 0.070 659.910 0.560 ;
        RECT 660.750 0.070 667.270 0.560 ;
        RECT 668.110 0.070 674.630 0.560 ;
        RECT 675.470 0.070 681.990 0.560 ;
        RECT 682.830 0.070 689.350 0.560 ;
        RECT 690.190 0.070 696.710 0.560 ;
        RECT 697.550 0.070 704.070 0.560 ;
        RECT 704.910 0.070 711.430 0.560 ;
        RECT 712.270 0.070 718.790 0.560 ;
        RECT 719.630 0.070 726.150 0.560 ;
        RECT 726.990 0.070 733.510 0.560 ;
        RECT 734.350 0.070 740.870 0.560 ;
        RECT 741.710 0.070 748.230 0.560 ;
        RECT 749.070 0.070 755.590 0.560 ;
        RECT 756.430 0.070 762.950 0.560 ;
        RECT 763.790 0.070 770.310 0.560 ;
        RECT 771.150 0.070 777.670 0.560 ;
        RECT 778.510 0.070 785.030 0.560 ;
        RECT 785.870 0.070 792.390 0.560 ;
        RECT 793.230 0.070 806.740 0.560 ;
      LAYER met3 ;
        RECT 3.030 9.015 805.855 815.145 ;
      LAYER met4 ;
        RECT 3.055 811.200 800.105 815.145 ;
        RECT 3.055 11.735 20.640 811.200 ;
        RECT 23.040 11.735 23.940 811.200 ;
        RECT 26.340 11.735 174.240 811.200 ;
        RECT 176.640 11.735 177.540 811.200 ;
        RECT 179.940 11.735 327.840 811.200 ;
        RECT 330.240 11.735 331.140 811.200 ;
        RECT 333.540 11.735 481.440 811.200 ;
        RECT 483.840 11.735 484.740 811.200 ;
        RECT 487.140 11.735 635.040 811.200 ;
        RECT 637.440 11.735 638.340 811.200 ;
        RECT 640.740 11.735 788.640 811.200 ;
        RECT 791.040 11.735 791.940 811.200 ;
        RECT 794.340 11.735 800.105 811.200 ;
  END
END aes_wb_wrapper
END LIBRARY

